! (c) 2009  Infineon Technologies AG, Munich
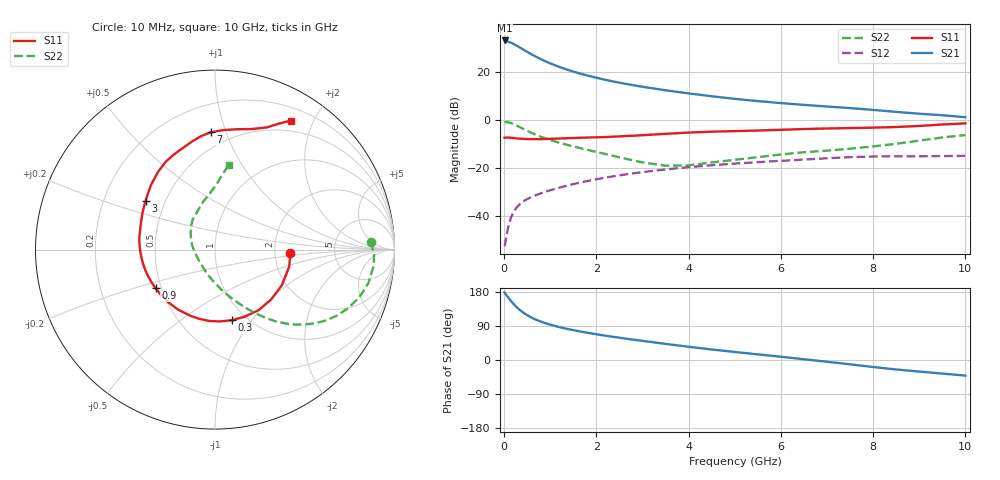
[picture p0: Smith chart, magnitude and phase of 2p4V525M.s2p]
! Infineon Technologies  Discrete & RF Semiconductors
! BFP420
! VCE =  4.5 V,  IC =  25 mA
! Common Emitter S-Parameters:  Nov 2009
# GHz  S  MA  R  50
!  f  S11  S21  S12  S22
! GHz  MAG  ANG  MAG  ANG  MAG  ANG  MAG  ANG
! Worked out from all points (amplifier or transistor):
!   46 points, 10 MHz to 10 GHz, reference 50 ohm
!   highest |S21| = 33.0 dB at 10 MHz (marker M1)
!   |S21| within 3 dB of that: start of sweep to 347.6 MHz
!   unconditionally stable (mu >= 1): start of sweep to 30.16 MHz; 1.685 GHz to end of sweep
!   at 300 MHz: K = 0.46, MSG = 33.3 dB, |S12| = -36.0 dB
!   at 1.7 GHz: K = 1.00, MAG = 22.2 dB, |S12| = -26.0 dB
!   at 10 GHz: K = 1.07, MAG = 6.5 dB, |S12| = -15.1 dB
!   lowest NFmin = 1.38 dB at 900 MHz
!   S11 on the Smith chart (normalised r, x): 10 MHz: 2.44, -0.11; 300 MHz: 0.86, -0.81; 900 MHz: 0.46, -0.24; 3 GHz: 0.39, +0.27; 7 GHz: 0.39, +0.89; 10 GHz: 0.36, +1.70
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0.01  0.4202 -2.6  44.77 178.4  0.0023 33.6  0.8693 2.8
0.02  0.4208 -4.8  43.51 175.8  0.0025 35.8  0.8862 -1.6
0.05  0.4239 -13.2  42.86 170.9  0.0038 52.6  0.8895 -5.6
0.1  0.4223 -28.1  41.82 163.0  0.0064 63.7  0.8749 -12.3
0.15  0.4183 -41.8  40.12 155.4  0.0092 64.8  0.8462 -18.4
0.2  0.4157 -54.2  38.12 148.4  0.0116 63.9  0.8103 -23.8
0.25  0.4086 -66.0  35.86 141.9  0.0139 62.4  0.7708 -28.6
0.3  0.4046 -76.7  33.74 136.1  0.0159 61.0  0.7296 -32.9
0.35  0.4011 -86.3  31.6 131.0  0.0176 59.8  0.6896 -36.6
0.45  0.3956 -102.5  27.66 122.0  0.0207 57.9  0.6162 -42.7
0.6  0.3927 -121.5  22.83 111.5  0.0246 56.3  0.5263 -49.6
0.7  0.3924 -131.5  20.28 105.9  0.0269 55.9  0.4786 -53.1
0.9  0.3951 -146.9  16.39 96.9  0.0315 55.6  0.4057 -58.7
1.2  0.4049 -163.5  12.53 86.7  0.0382 55.5  0.329 -66.0
1.7  0.4203 177.4  8.85 74.2  0.05 54.3  0.2476 -76.9
2.2  0.434 163.2  6.756 64.1  0.0619 51.6  0.1916 -88.5
3  0.4737 144.8  4.842 50.5  0.0805 45.5  0.1284 -116.1
3.5  0.5064 134.9  4.091 42.5  0.0915 41.2  0.1095 -142.1
5.5  0.5925 107.9  2.435 14.9  0.1298 23.1  0.1653 145.1
7  0.6542 91.9  1.877 -4.6  0.1564 9.3  0.2255 117.9
8.5  0.7015 73.2  1.45 -25.0  0.1715 -7.6  0.3139 95.3
10  0.835 59.4  1.122 -41.2  0.1758 -18.9  0.4772 80.8
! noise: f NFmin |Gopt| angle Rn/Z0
0.9  1.38  0.22  -154  0.13
1.8  1.65  0.29  -143  0.13
2.4  1.81  0.26  -138  0.17
3  1.83  0.34  -129  0.18
4  1.97  0.45  -112  0.27
5  2.4  0.49  -95  0.44
6  2.85  0.54  -84  0.65
